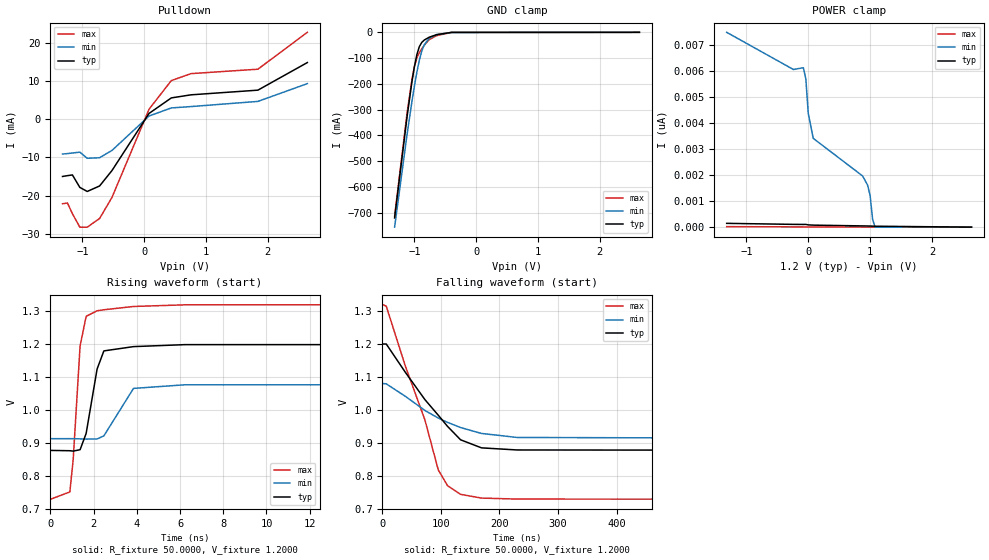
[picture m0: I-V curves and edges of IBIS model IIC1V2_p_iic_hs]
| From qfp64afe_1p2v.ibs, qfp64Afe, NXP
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[Model] IIC1V2_p_iic_hs
|   Model IIC1V2_p_iic_hs
| This model was characterised for following simulation conditions:
| External (pad) voltage:
|   - Typ: 1.2V,   - Min: 1.08V,   - Max: 1.32V
| Library cells for typ/min/max conditions are connected as defined below:
|  IO - External Pad
|  A - Core Input
|  EN - Output Buffer Enable
|  BOOST - vdde
|  ECS - gnd
|  EGP - gnd
|  ENZI - vdd
|  EPD - gnd
|  EPUN - vdd
|  ZI - NC
|  ZIF - NC
|  gnd - gnd
|  gnde - gnde
|  vdd - vdd
|  vdde - vdde
| All other pins connected to ground
Model_type I/O_open_drain
Polarity   Non-Inverting
Enable   Active-Low
Vinl =   0.5400V
Vinh =   1.2600V
Vmeas =  0.9000V
Cref =   0.0F
Rref =   1.0000k
Vref =   1.2000V
C_comp   3.6477pF   3.5140pF   3.7674pF
|C_comp_pullup   0.9543pF   0.9094pF   0.9729pF
|C_comp_pulldown   2.3399pF   2.4911pF   2.1962pF
[Model Spec]
| variable   typ   min   max
Vinh   0.3600V   0.3240V   0.3960V
Vinl   0.8400V   0.7560V   0.9240V
Vmeas   0.6000V   0.5400V   0.6600V
Vref   1.2000V   1.0800V   1.3200V
Cref   0.0F   0.0F   0.0F
Rref   1.0000k   1.0000k   1.0000k
[Temperature Range]   25.0000   0.1250k   -40.0000
[Voltage Range]   1.2000V   1.0800V   1.3200V
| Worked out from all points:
|   slope of the pulldown table from 0 to 0.18 V, typ, clamps not added: 58.3 ohm
|   GND clamp passes 1 mA (typ) near -0.45 V on its own axis
|   rising waveform, R_fixture 50.0000, V_fixture 1.2000: 20-80 % time 502ps typ, 802ps min, 333ps max; typ from 0.877 V to 1.2 V
|   falling waveform, R_fixture 50.0000, V_fixture 1.2000: 20-80 % time 83.3ns typ, 98.9ns min, 62.7ns max; typ from 1.2 V to 0.877 V
[Pulldown]
|Voltage   I(typ)   I(min)   I(max)
-1.32V    -14.96mA   -9.099mA   -22.09mA
-1.24V    -14.75mA   -8.982mA   -21.89mA
-1.16V    -14.56mA   -8.83mA    -24.7mA
-1.04V    -17.82mA   -8.609mA   -28.21mA
-920mV    -18.88mA   -10.21mA   -28.21mA
-720mV    -17.44mA   -10.07mA   -25.94mA
-520mV    -13.41mA   -8.157mA   -20.44mA
80mV      1.521mA    840uA      2.628mA
440mV     5.569mA    2.951mA    10.1mA
760mV     6.377mA    3.307mA    11.92mA
1.84V     7.596mA    4.654mA    13.07mA
2.64V     14.81mA    9.301mA    22.71mA
[GND_clamp]
|Voltage   I(typ)   I(min)   I(max)
-1.32V    -720.7mA   -756.4mA   -713.8mA
-1.12V    -330.9mA   -399.5mA   -316.8mA
-1.04V    -192.4mA   -269.2mA   -184.4mA
-1V       -133.6mA   -209.3mA   -133.5mA
-960mV    -86.73mA   -154.7mA   -99.45mA
-920mV    -55.68mA   -108.2mA   -79.01mA
-880mV    -39.01mA   -72.34mA   -63.7mA
-840mV    -29.9mA    -47.99mA   -50.25mA
-760mV    -18.92mA   -23.38mA   -28.31mA
-640mV    -9.212mA   -8.622mA   -12.72mA
-400mV    -328.4uA   -396.6uA   -434.3uA
2.64V     0A         0A         0A
[POWER_clamp]
|Voltage   I(typ)   I(min)   I(max)
-1.32V    146.2pA    7.487nA    20.6pA
-240mV    107.2pA    6.058nA    10.71pA
-80mV     104.3pA    6.128nA    10.43pA
-40mV     105.3pA    5.7nA      9.002pA
0V        87.49pA    4.363nA    8.131pA
80mV      77.4pA     3.412nA    7.54pA
880mV     48.09pA    1.964nA    2.626pA
960mV     44.51pA    1.611nA    2.139pA
1V        42.37pA    1.211nA    1.894pA
1.04V     39.75pA    304.3pA    1.646pA
1.08V     36.09pA    0A         1.394pA
2.64V     0A         0A         0A
[Ramp]
| variable   typ   min   max
dV/dt_r  0.1940/0.5018n   0.1007/0.8020n   0.3553/0.3326n
dV/dt_f  0.1940/83.3256n   0.1006/98.9726n   0.3552/62.6671n
R_load = 50.0000
[Rising Waveform]
R_fixture= 50.0000
V_fixture= 1.2000
V_fixture_min= 1.0800
V_fixture_max= 1.3200
|time   V(typ)   V(min)   V(max)
0s        876.6mV    912.2mV    727.9mV
906ps     875.6mV    912.3mV    750.4mV
1.06ns    874.5mV    912.2mV    848.8mV
1.379ns   878.7mV    911.7mV    1.194V
1.659ns   928.2mV    911mV      1.284V
2.166ns   1.124V     911.3mV    1.301V
2.479ns   1.179V     920.8mV    1.304V
3.849ns   1.192V     1.065V     1.314V
6.228ns   1.198V     1.076V     1.319V
1us       1.2V       1.08V      1.32V
[Falling Waveform]
R_fixture= 50.0000
V_fixture= 1.2000
V_fixture_min= 1.0800
V_fixture_max= 1.3200
|time   V(typ)   V(min)   V(max)
0s        1.2V       1.08V      1.32V
6.631ns   1.2V       1.079V     1.315V
39.25ns   1.114V     1.041V     1.133V
72.68ns   1.031V     998mV      969.3mV
95.48ns   983.6mV    975mV      817.5mV
111.3ns   949.7mV    961.8mV    769.6mV
133.6ns   908.9mV    946.1mV    743.1mV
169.3ns   884.4mV    928.2mV    731.8mV
230ns     878mV      916mV      728.8mV
1us       876.7mV    912.3mV    728mV
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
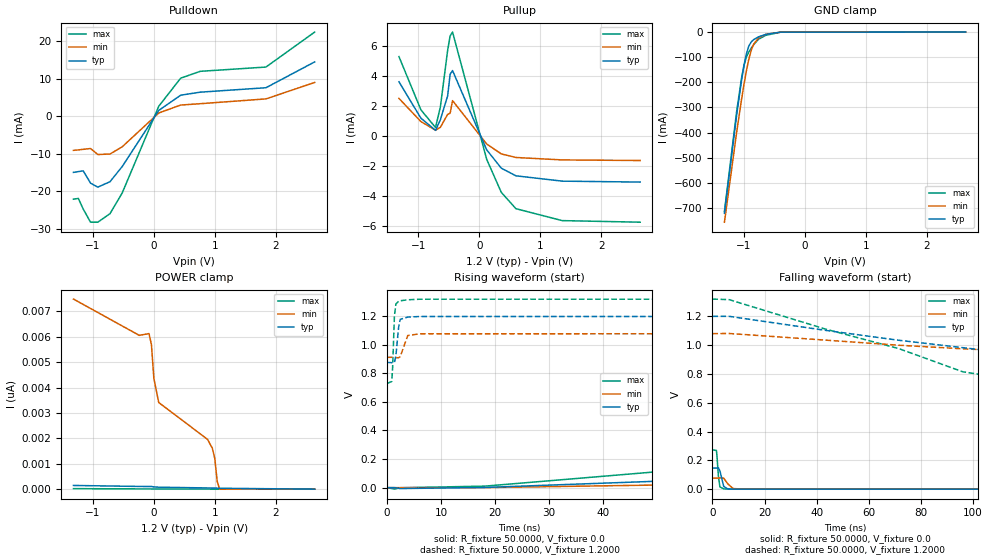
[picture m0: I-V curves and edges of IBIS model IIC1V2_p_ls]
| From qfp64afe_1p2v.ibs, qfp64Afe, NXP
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[Model] IIC1V2_p_ls
|   Model IIC1V2_p_ls
| This model was characterised for following simulation conditions:
| External (pad) voltage:
|   - Typ: 1.2V,   - Min: 1.08V,   - Max: 1.32V
| Library cells for typ/min/max conditions are connected as defined below:
|  IO - External Pad
|  A - Core Input
|  EN - Output Buffer Enable
|  BOOST - vdde
|  EGP - vdd
|  EHS - gnd
|  ENZI - vdd
|  EPD - gnd
|  EPUN - vdd
|  ZI - NC
|  ZIF - NC
|  gnd - gnd
|  gnde - gnde
|  vdd - vdd
|  vdde - vdde
| All other pins connected to ground
Model_type I/O
Polarity   Non-Inverting
Enable   Active-Low
Vinl =   0.5400V
Vinh =   1.2600V
Vmeas =  0.9000V
Cref =   0.0F
Rref =   1.0000k
Vref =   0.0V
C_comp   3.6473pF   3.5138pF   3.7665pF
|C_comp_pullup   0.9537pF   0.9078pF   0.9727pF
|C_comp_pulldown   2.3401pF   2.4920pF   2.1963pF
[Model Spec]
| variable   typ   min   max
Vinh   0.3600V   0.3240V   0.3960V
Vinl   0.8400V   0.7560V   0.9240V
Vmeas   0.6000V   0.5400V   0.6600V
[Temperature Range]   25.0000   0.1250k   -40.0000
[Voltage Range]   1.2000V   1.0800V   1.3200V
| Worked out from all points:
|   slope of the pulldown table from 0 to 0.18 V, typ, clamps not added: 58.3 ohm
|   slope of the pullup table from 0 to 0.18 V, typ, clamps not added: 138 ohm
|   GND clamp passes 1 mA (typ) near -0.45 V on its own axis
|   rising waveform, R_fixture 50.0000, V_fixture 0.0: 20-80 % time 73.3ns typ, 82.8ns min, 61.7ns max; typ from 0 V to 0.146 V
|   rising waveform, R_fixture 50.0000, V_fixture 1.2000: 20-80 % time 495ps typ, 787ps min, 328ps max; typ from 0.877 V to 1.2 V
|   falling waveform, R_fixture 50.0000, V_fixture 0.0: 20-80 % time 1.12ns typ, 1.9ns min, 700ps max; typ from 0.146 V to 0 V
|   falling waveform, R_fixture 50.0000, V_fixture 1.2000: 20-80 % time 83.3ns typ, 98.9ns min, 62.7ns max; typ from 1.2 V to 0.877 V
[Pulldown]
|Voltage   I(typ)   I(min)   I(max)
-1.32V    -14.96mA   -9.099mA   -22.09mA
-1.24V    -14.75mA   -8.982mA   -21.89mA
-1.16V    -14.56mA   -8.83mA    -24.7mA
-1.04V    -17.82mA   -8.609mA   -28.21mA
-920mV    -18.88mA   -10.21mA   -28.21mA
-720mV    -17.44mA   -10.07mA   -25.94mA
-520mV    -13.41mA   -8.157mA   -20.44mA
80mV      1.521mA    840uA      2.628mA
440mV     5.569mA    2.951mA    10.1mA
760mV     6.377mA    3.307mA    11.92mA
1.84V     7.559mA    4.586mA    13.06mA
2.64V     14.43mA    8.958mA    22.36mA
[Pullup]
|Voltage   I(typ)   I(min)   I(max)
-1.32V    3.599mA    2.494mA    5.272mA
-960mV    1.183mA    954.7uA    1.735mA
-720mV    366.8uA    380.1uA    560.7uA
-640mV    1.076mA    572uA      1.919mA
-520mV    2.672mA    1.434mA    5.709mA
-480mV    4.096mA    1.502mA    6.65mA
-440mV    4.343mA    2.346mA    6.902mA
120mV     -924.8uA   -536.9uA   -1.554mA
360mV     -2.143mA   -1.197mA   -3.751mA
600mV     -2.653mA   -1.434mA   -4.838mA
1.36V     -3.007mA   -1.596mA   -5.631mA
2.64V     -3.069mA   -1.636mA   -5.736mA
[GND_clamp]
|Voltage   I(typ)   I(min)   I(max)
-1.32V    -720.7mA   -756.4mA   -713.8mA
-1.12V    -330.9mA   -399.5mA   -316.8mA
-1.04V    -192.4mA   -269.2mA   -184.4mA
-1V       -133.6mA   -209.3mA   -133.5mA
-960mV    -86.73mA   -154.7mA   -99.45mA
-920mV    -55.68mA   -108.2mA   -79.01mA
-880mV    -39.01mA   -72.34mA   -63.7mA
-840mV    -29.9mA    -47.99mA   -50.25mA
-760mV    -18.92mA   -23.38mA   -28.31mA
-640mV    -9.212mA   -8.622mA   -12.72mA
-400mV    -328.4uA   -396.6uA   -434.3uA
2.64V     0A         0A         0A
[POWER_clamp]
|Voltage   I(typ)   I(min)   I(max)
-1.32V    146.2pA    7.487nA    20.6pA
-240mV    107.2pA    6.058nA    10.71pA
-80mV     104.3pA    6.128nA    10.43pA
-40mV     105.3pA    5.7nA      9.002pA
0V        87.49pA    4.363nA    8.131pA
80mV      77.4pA     3.412nA    7.54pA
880mV     48.09pA    1.964nA    2.626pA
960mV     44.51pA    1.611nA    2.139pA
1V        42.37pA    1.211nA    1.894pA
1.04V     39.75pA    304.3pA    1.646pA
1.08V     36.09pA    0A         1.394pA
2.64V     0A         0A         0A
[Ramp]
| variable   typ   min   max
dV/dt_r  87.7367m/73.3638n   46.3941m/82.7765n   0.1636/61.7560n
dV/dt_f  0.1940/83.2849n   0.1006/98.9600n   0.3552/62.6860n
R_load = 50.0000
[Rising Waveform]
R_fixture= 50.0000
V_fixture= 0.0
V_fixture_min= 0.0
V_fixture_max= 0.0
|time   V(typ)   V(min)   V(max)
0s        663.7pV    60.46nV    39.17pV
1.445ns   -661.9uV   126.7uV    -10.83mV
2.434ns   -6.509mV   -500.2uV   -616.3uV
18.13ns   1.187mV    309.2uV    10.36mV
57.57ns   55.19mV    22.26mV    135.2mV
97.04ns   102.6mV    47.31mV    224.2mV
116.5ns   119mV      56.56mV    249.1mV
149ns     135.6mV    67.15mV    265.8mV
252.5ns   145.7mV    76.41mV    272.5mV
1us       146.2mV    77.32mV    272.7mV
[Rising Waveform]
R_fixture= 50.0000
V_fixture= 1.2000
V_fixture_min= 1.0800
V_fixture_max= 1.3200
|time   V(typ)   V(min)   V(max)
0s        876.6mV    912.2mV    727.9mV
902.2ps   874.8mV    912.4mV    743.3mV
1.062ns   872.6mV    912.3mV    843.4mV
1.394ns   875.4mV    911.3mV    1.202V
1.67ns    926.1mV    909.9mV    1.286V
2.162ns   1.12V      908.9mV    1.304V
2.466ns   1.178V     917.1mV    1.308V
3.862ns   1.194V     1.065V     1.315V
6.134ns   1.198V     1.077V     1.319V
1us       1.2V       1.08V      1.32V
[Falling Waveform]
R_fixture= 50.0000
V_fixture= 0.0
V_fixture_min= 0.0
V_fixture_max= 0.0
|time   V(typ)   V(min)   V(max)
0s        146.3mV    77.36mV    272.8mV
1.538ns   146.4mV    77.36mV    268.8mV
1.722ns   147mV      77.34mV    240.2mV
2.304ns   148.8mV    77.28mV    90.92mV
2.892ns   127.1mV    77.84mV    15.63mV
4.35ns    19.3mV     76.26mV    1.996mV
5.878ns   1.798mV    37.55mV    745.5uV
7.946ns   487.2uV    4.089mV    481.2uV
12.72ns   263uV      265.1uV    241.1uV
1us       25.89nV    103.3nV    14.92nV
[Falling Waveform]
R_fixture= 50.0000
V_fixture= 1.2000
V_fixture_min= 1.0800
V_fixture_max= 1.3200
|time   V(typ)   V(min)   V(max)
0s        1.2V       1.08V      1.32V
6.433ns   1.2V       1.081V     1.316V
43.29ns   1.103V     1.035V     1.112V
71.43ns   1.034V     999.5mV    976.4mV
96ns      982.7mV    974.6mV    815.2mV
113.7ns   944.6mV    960.1mV    765.2mV
137ns     904.7mV    944.2mV    741.1mV
175.9ns   882.8mV    926mV      731mV
266.1ns   877.4mV    914mV      728.5mV
1us       876.7mV    912.3mV    728mV
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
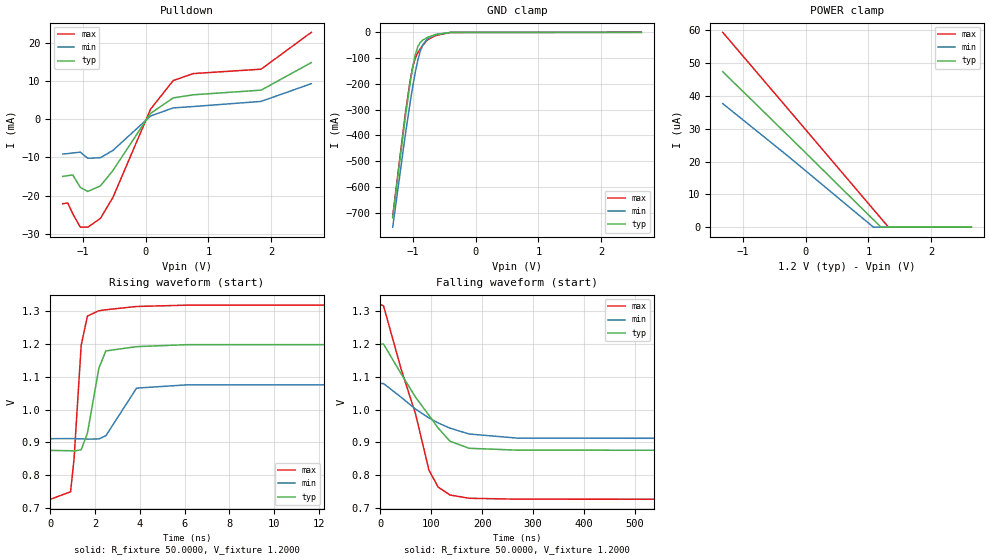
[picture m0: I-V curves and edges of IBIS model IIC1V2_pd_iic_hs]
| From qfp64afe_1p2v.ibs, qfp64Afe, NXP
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[Model] IIC1V2_pd_iic_hs
|   Model IIC1V2_pd_iic_hs
| This model was characterised for following simulation conditions:
| External (pad) voltage:
|   - Typ: 1.2V,   - Min: 1.08V,   - Max: 1.32V
| Library cells for typ/min/max conditions are connected as defined below:
|  IO - External Pad
|  A - Core Input
|  EN - Output Buffer Enable
|  BOOST - vdde
|  ECS - gnd
|  EGP - gnd
|  ENZI - vdd
|  EPD - vdd
|  EPUN - vdd
|  ZI - NC
|  ZIF - NC
|  gnd - gnd
|  gnde - gnde
|  vdd - vdd
|  vdde - vdde
| All other pins connected to ground
Model_type I/O_open_drain
Polarity   Non-Inverting
Enable   Active-Low
Vinl =   0.5400V
Vinh =   1.2600V
Vmeas =  0.9000V
Cref =   0.0F
Rref =   1.0000k
Vref =   1.2000V
C_comp   3.6168pF   3.4770pF   3.7425pF
|C_comp_pullup   0.9409pF   0.9008pF   0.9551pF
|C_comp_pulldown   2.3238pF   2.4763pF   2.1787pF
[Model Spec]
| variable   typ   min   max
Vinh   0.3600V   0.3240V   0.3960V
Vinl   0.8400V   0.7560V   0.9240V
Vmeas   0.6000V   0.5400V   0.6600V
Vref   1.2000V   1.0800V   1.3200V
Cref   0.0F   0.0F   0.0F
Rref   1.0000k   1.0000k   1.0000k
[Temperature Range]   25.0000   0.1250k   -40.0000
[Voltage Range]   1.2000V   1.0800V   1.3200V
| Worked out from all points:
|   slope of the pulldown table from 0 to 0.18 V, typ, clamps not added: 58.3 ohm
|   GND clamp passes 1 mA (typ) near -0.45 V on its own axis
|   rising waveform, R_fixture 50.0000, V_fixture 1.2000: 20-80 % time 501ps typ, 801ps min, 332ps max; typ from 0.876 V to 1.2 V
|   falling waveform, R_fixture 50.0000, V_fixture 1.2000: 20-80 % time 83.2ns typ, 98.9ns min, 62.5ns max; typ from 1.2 V to 0.876 V
[Pulldown]
|Voltage   I(typ)   I(min)   I(max)
-1.32V    -14.96mA   -9.099mA   -22.09mA
-1.24V    -14.75mA   -8.982mA   -21.89mA
-1.16V    -14.56mA   -8.83mA    -24.7mA
-1.04V    -17.82mA   -8.609mA   -28.21mA
-920mV    -18.88mA   -10.21mA   -28.21mA
-720mV    -17.44mA   -10.07mA   -25.94mA
-520mV    -13.41mA   -8.157mA   -20.44mA
80mV      1.521mA    840uA      2.628mA
440mV     5.569mA    2.951mA    10.1mA
760mV     6.377mA    3.307mA    11.92mA
1.84V     7.592mA    4.649mA    13.07mA
2.64V     14.79mA    9.287mA    22.7mA
[GND_clamp]
|Voltage   I(typ)   I(min)   I(max)
-1.32V    -720.7mA   -756.5mA   -713.8mA
-1.12V    -330.9mA   -399.5mA   -316.8mA
-1.04V    -192.4mA   -269.2mA   -184.4mA
-1V       -133.6mA   -209.3mA   -133.5mA
-960mV    -86.74mA   -154.7mA   -99.46mA
-920mV    -55.69mA   -108.2mA   -79.02mA
-880mV    -39.02mA   -72.35mA   -63.71mA
-840mV    -29.9mA    -48mA      -50.26mA
-760mV    -18.93mA   -23.39mA   -28.32mA
-640mV    -9.22mA    -8.628mA   -12.73mA
-400mV    -335.3uA   -402.3uA   -442.6uA
2.64V     0A         0A         0A
[POWER_clamp]
|Voltage   I(typ)   I(min)   I(max)
-1.32V    47.4uA     37.67uA    59.39uA
-280mV    27.94uA    21.65uA    36.04uA
1.08V     2.274uA    0A         5.413uA
1.2V      0A         0A         2.707uA
1.32V     0A         0A         0A
2.64V     0A         0A         0A
[Ramp]
| variable   typ   min   max
dV/dt_r  0.1938/0.5014n   0.1006/0.8017n   0.3548/0.3320n
dV/dt_f  0.1938/83.2106n   0.1006/98.8181n   0.3548/62.5201n
R_load = 50.0000
[Rising Waveform]
R_fixture= 50.0000
V_fixture= 1.2000
V_fixture_min= 1.0800
V_fixture_max= 1.3200
|time   V(typ)   V(min)   V(max)
0s        875.8mV    911.4mV    727.2mV
907ps     874.8mV    911.6mV    750.1mV
1.062ns   873.7mV    911.5mV    850mV
1.381ns   878mV      911mV      1.195V
1.661ns   928.2mV    910.2mV    1.284V
2.17ns    1.125V     910.6mV    1.3V
2.483ns   1.178V     920.3mV    1.303V
3.857ns   1.191V     1.065V     1.313V
6.11ns    1.197V     1.075V     1.317V
1us       1.199V     1.079V     1.319V
[Falling Waveform]
R_fixture= 50.0000
V_fixture= 1.2000
V_fixture_min= 1.0800
V_fixture_max= 1.3200
|time   V(typ)   V(min)   V(max)
0s        1.199V     1.079V     1.319V
6.361ns   1.199V     1.079V     1.315V
41.12ns   1.108V     1.037V     1.122V
69.41ns   1.037V     1.001V     985.5mV
95.48ns   982.5mV    974.3mV    816mV
113.6ns   943.7mV    959.3mV    764.4mV
136.9ns   903.6mV    943.3mV    740.3mV
174.6ns   882.2mV    925.6mV    730.4mV
268.4ns   876.6mV    913.2mV    727.7mV
1us       875.9mV    911.5mV    727.2mV
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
